VERSION 5.7 ;
BUSBITCHARS "[]" ;
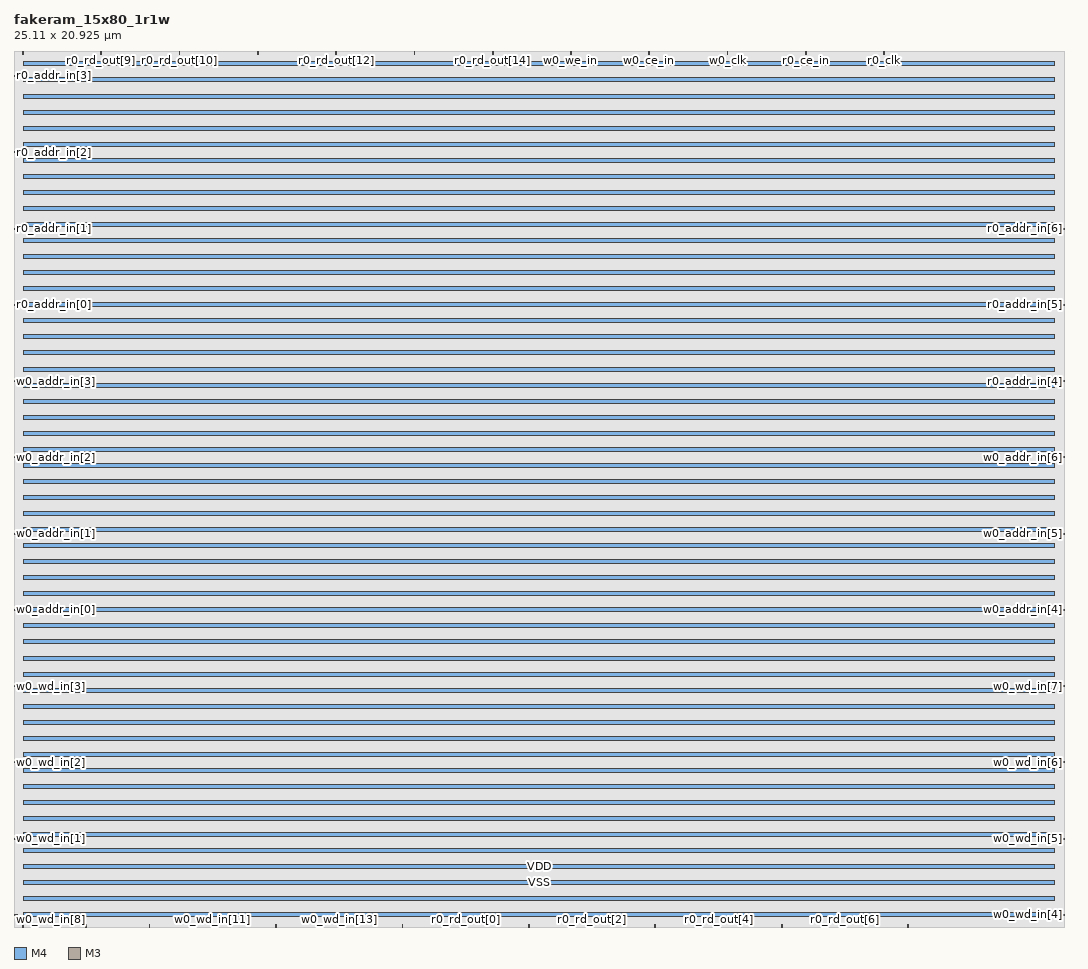
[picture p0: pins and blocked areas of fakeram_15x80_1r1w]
MACRO fakeram_15x80_1r1w
  FOREIGN fakeram_15x80_1r1w 0 0 ;
  SYMMETRY X Y R90 ;
  SIZE 25.110 BY 20.925 ;
  CLASS BLOCK ;
  PIN w0_wd_in[0]
    DIRECTION INPUT ;
    USE SIGNAL ;
    SHAPE ABUTMENT ;
    PORT
      LAYER M4 ;
      RECT 0.000 0.276 0.072 0.300 ;
    END
  END w0_wd_in[0]
  PIN w0_wd_in[1]
    DIRECTION INPUT ;
    USE SIGNAL ;
    SHAPE ABUTMENT ;
    PORT
      LAYER M4 ;
      RECT 0.000 2.100 0.072 2.124 ;
    END
  END w0_wd_in[1]
  PIN w0_wd_in[2]
    DIRECTION INPUT ;
    USE SIGNAL ;
    SHAPE ABUTMENT ;
    PORT
      LAYER M4 ;
      RECT 0.000 3.924 0.072 3.948 ;
    END
  END w0_wd_in[2]
  PIN w0_wd_in[3]
    DIRECTION INPUT ;
    USE SIGNAL ;
    SHAPE ABUTMENT ;
    PORT
      LAYER M4 ;
      RECT 0.000 5.748 0.072 5.772 ;
    END
  END w0_wd_in[3]
  PIN w0_wd_in[4]
    DIRECTION INPUT ;
    USE SIGNAL ;
    SHAPE ABUTMENT ;
    PORT
      LAYER M4 ;
      RECT 25.038 0.276 25.110 0.300 ;
    END
  END w0_wd_in[4]
  PIN w0_wd_in[5]
    DIRECTION INPUT ;
    USE SIGNAL ;
    SHAPE ABUTMENT ;
    PORT
      LAYER M4 ;
      RECT 25.038 2.100 25.110 2.124 ;
    END
  END w0_wd_in[5]
  PIN w0_wd_in[6]
    DIRECTION INPUT ;
    USE SIGNAL ;
    SHAPE ABUTMENT ;
    PORT
      LAYER M4 ;
      RECT 25.038 3.924 25.110 3.948 ;
    END
  END w0_wd_in[6]
  PIN w0_wd_in[7]
    DIRECTION INPUT ;
    USE SIGNAL ;
    SHAPE ABUTMENT ;
    PORT
      LAYER M4 ;
      RECT 25.038 5.748 25.110 5.772 ;
    END
  END w0_wd_in[7]
  PIN w0_wd_in[8]
    DIRECTION INPUT ;
    USE SIGNAL ;
    SHAPE ABUTMENT ;
    PORT
      LAYER M3 ;
      RECT 0.207 0.000 0.225 0.054 ;
    END
  END w0_wd_in[8]
  PIN w0_wd_in[9]
    DIRECTION INPUT ;
    USE SIGNAL ;
    SHAPE ABUTMENT ;
    PORT
      LAYER M3 ;
      RECT 1.719 0.000 1.737 0.054 ;
    END
  END w0_wd_in[9]
  PIN w0_wd_in[10]
    DIRECTION INPUT ;
    USE SIGNAL ;
    SHAPE ABUTMENT ;
    PORT
      LAYER M3 ;
      RECT 3.231 0.000 3.249 0.054 ;
    END
  END w0_wd_in[10]
  PIN w0_wd_in[11]
    DIRECTION INPUT ;
    USE SIGNAL ;
    SHAPE ABUTMENT ;
    PORT
      LAYER M3 ;
      RECT 4.743 0.000 4.761 0.054 ;
    END
  END w0_wd_in[11]
  PIN w0_wd_in[12]
    DIRECTION INPUT ;
    USE SIGNAL ;
    SHAPE ABUTMENT ;
    PORT
      LAYER M3 ;
      RECT 6.255 0.000 6.273 0.054 ;
    END
  END w0_wd_in[12]
  PIN w0_wd_in[13]
    DIRECTION INPUT ;
    USE SIGNAL ;
    SHAPE ABUTMENT ;
    PORT
      LAYER M3 ;
      RECT 7.767 0.000 7.785 0.054 ;
    END
  END w0_wd_in[13]
  PIN w0_wd_in[14]
    DIRECTION INPUT ;
    USE SIGNAL ;
    SHAPE ABUTMENT ;
    PORT
      LAYER M3 ;
      RECT 9.279 0.000 9.297 0.054 ;
    END
  END w0_wd_in[14]
  PIN r0_rd_out[0]
    DIRECTION OUTPUT ;
    USE SIGNAL ;
    SHAPE ABUTMENT ;
    PORT
      LAYER M3 ;
      RECT 10.791 0.000 10.809 0.054 ;
    END
  END r0_rd_out[0]
  PIN r0_rd_out[1]
    DIRECTION OUTPUT ;
    USE SIGNAL ;
    SHAPE ABUTMENT ;
    PORT
      LAYER M3 ;
      RECT 12.303 0.000 12.321 0.054 ;
    END
  END r0_rd_out[1]
  PIN r0_rd_out[2]
    DIRECTION OUTPUT ;
    USE SIGNAL ;
    SHAPE ABUTMENT ;
    PORT
      LAYER M3 ;
      RECT 13.815 0.000 13.833 0.054 ;
    END
  END r0_rd_out[2]
  PIN r0_rd_out[3]
    DIRECTION OUTPUT ;
    USE SIGNAL ;
    SHAPE ABUTMENT ;
    PORT
      LAYER M3 ;
      RECT 15.327 0.000 15.345 0.054 ;
    END
  END r0_rd_out[3]
  PIN r0_rd_out[4]
    DIRECTION OUTPUT ;
    USE SIGNAL ;
    SHAPE ABUTMENT ;
    PORT
      LAYER M3 ;
      RECT 16.839 0.000 16.857 0.054 ;
    END
  END r0_rd_out[4]
  PIN r0_rd_out[5]
    DIRECTION OUTPUT ;
    USE SIGNAL ;
    SHAPE ABUTMENT ;
    PORT
      LAYER M3 ;
      RECT 18.351 0.000 18.369 0.054 ;
    END
  END r0_rd_out[5]
  PIN r0_rd_out[6]
    DIRECTION OUTPUT ;
    USE SIGNAL ;
    SHAPE ABUTMENT ;
    PORT
      LAYER M3 ;
      RECT 19.863 0.000 19.881 0.054 ;
    END
  END r0_rd_out[6]
  PIN r0_rd_out[7]
    DIRECTION OUTPUT ;
    USE SIGNAL ;
    SHAPE ABUTMENT ;
    PORT
      LAYER M3 ;
      RECT 21.375 0.000 21.393 0.054 ;
    END
  END r0_rd_out[7]
  PIN r0_rd_out[8]
    DIRECTION OUTPUT ;
    USE SIGNAL ;
    SHAPE ABUTMENT ;
    PORT
      LAYER M3 ;
      RECT 0.207 20.871 0.225 20.925 ;
    END
  END r0_rd_out[8]
  PIN r0_rd_out[9]
    DIRECTION OUTPUT ;
    USE SIGNAL ;
    SHAPE ABUTMENT ;
    PORT
      LAYER M3 ;
      RECT 2.079 20.871 2.097 20.925 ;
    END
  END r0_rd_out[9]
  PIN r0_rd_out[10]
    DIRECTION OUTPUT ;
    USE SIGNAL ;
    SHAPE ABUTMENT ;
    PORT
      LAYER M3 ;
      RECT 3.951 20.871 3.969 20.925 ;
    END
  END r0_rd_out[10]
  PIN r0_rd_out[11]
    DIRECTION OUTPUT ;
    USE SIGNAL ;
    SHAPE ABUTMENT ;
    PORT
      LAYER M3 ;
      RECT 5.823 20.871 5.841 20.925 ;
    END
  END r0_rd_out[11]
  PIN r0_rd_out[12]
    DIRECTION OUTPUT ;
    USE SIGNAL ;
    SHAPE ABUTMENT ;
    PORT
      LAYER M3 ;
      RECT 7.695 20.871 7.713 20.925 ;
    END
  END r0_rd_out[12]
  PIN r0_rd_out[13]
    DIRECTION OUTPUT ;
    USE SIGNAL ;
    SHAPE ABUTMENT ;
    PORT
      LAYER M3 ;
      RECT 9.567 20.871 9.585 20.925 ;
    END
  END r0_rd_out[13]
  PIN r0_rd_out[14]
    DIRECTION OUTPUT ;
    USE SIGNAL ;
    SHAPE ABUTMENT ;
    PORT
      LAYER M3 ;
      RECT 11.439 20.871 11.457 20.925 ;
    END
  END r0_rd_out[14]
  PIN w0_addr_in[0]
    DIRECTION INPUT ;
    USE SIGNAL ;
    SHAPE ABUTMENT ;
    PORT
      LAYER M4 ;
      RECT 0.000 7.572 0.072 7.596 ;
    END
  END w0_addr_in[0]
  PIN w0_addr_in[1]
    DIRECTION INPUT ;
    USE SIGNAL ;
    SHAPE ABUTMENT ;
    PORT
      LAYER M4 ;
      RECT 0.000 9.396 0.072 9.420 ;
    END
  END w0_addr_in[1]
  PIN w0_addr_in[2]
    DIRECTION INPUT ;
    USE SIGNAL ;
    SHAPE ABUTMENT ;
    PORT
      LAYER M4 ;
      RECT 0.000 11.220 0.072 11.244 ;
    END
  END w0_addr_in[2]
  PIN w0_addr_in[3]
    DIRECTION INPUT ;
    USE SIGNAL ;
    SHAPE ABUTMENT ;
    PORT
      LAYER M4 ;
      RECT 0.000 13.044 0.072 13.068 ;
    END
  END w0_addr_in[3]
  PIN w0_addr_in[4]
    DIRECTION INPUT ;
    USE SIGNAL ;
    SHAPE ABUTMENT ;
    PORT
      LAYER M4 ;
      RECT 25.038 7.572 25.110 7.596 ;
    END
  END w0_addr_in[4]
  PIN w0_addr_in[5]
    DIRECTION INPUT ;
    USE SIGNAL ;
    SHAPE ABUTMENT ;
    PORT
      LAYER M4 ;
      RECT 25.038 9.396 25.110 9.420 ;
    END
  END w0_addr_in[5]
  PIN w0_addr_in[6]
    DIRECTION INPUT ;
    USE SIGNAL ;
    SHAPE ABUTMENT ;
    PORT
      LAYER M4 ;
      RECT 25.038 11.220 25.110 11.244 ;
    END
  END w0_addr_in[6]
  PIN r0_addr_in[0]
    DIRECTION INPUT ;
    USE SIGNAL ;
    SHAPE ABUTMENT ;
    PORT
      LAYER M4 ;
      RECT 0.000 14.868 0.072 14.892 ;
    END
  END r0_addr_in[0]
  PIN r0_addr_in[1]
    DIRECTION INPUT ;
    USE SIGNAL ;
    SHAPE ABUTMENT ;
    PORT
      LAYER M4 ;
      RECT 0.000 16.692 0.072 16.716 ;
    END
  END r0_addr_in[1]
  PIN r0_addr_in[2]
    DIRECTION INPUT ;
    USE SIGNAL ;
    SHAPE ABUTMENT ;
    PORT
      LAYER M4 ;
      RECT 0.000 18.516 0.072 18.540 ;
    END
  END r0_addr_in[2]
  PIN r0_addr_in[3]
    DIRECTION INPUT ;
    USE SIGNAL ;
    SHAPE ABUTMENT ;
    PORT
      LAYER M4 ;
      RECT 0.000 20.340 0.072 20.364 ;
    END
  END r0_addr_in[3]
  PIN r0_addr_in[4]
    DIRECTION INPUT ;
    USE SIGNAL ;
    SHAPE ABUTMENT ;
    PORT
      LAYER M4 ;
      RECT 25.038 13.044 25.110 13.068 ;
    END
  END r0_addr_in[4]
  PIN r0_addr_in[5]
    DIRECTION INPUT ;
    USE SIGNAL ;
    SHAPE ABUTMENT ;
    PORT
      LAYER M4 ;
      RECT 25.038 14.868 25.110 14.892 ;
    END
  END r0_addr_in[5]
  PIN r0_addr_in[6]
    DIRECTION INPUT ;
    USE SIGNAL ;
    SHAPE ABUTMENT ;
    PORT
      LAYER M4 ;
      RECT 25.038 16.692 25.110 16.716 ;
    END
  END r0_addr_in[6]
  PIN w0_we_in
    DIRECTION INPUT ;
    USE SIGNAL ;
    SHAPE ABUTMENT ;
    PORT
      LAYER M3 ;
      RECT 13.311 20.871 13.329 20.925 ;
    END
  END w0_we_in
  PIN w0_ce_in
    DIRECTION INPUT ;
    USE SIGNAL ;
    SHAPE ABUTMENT ;
    PORT
      LAYER M3 ;
      RECT 15.183 20.871 15.201 20.925 ;
    END
  END w0_ce_in
  PIN w0_clk
    DIRECTION INPUT ;
    USE SIGNAL ;
    SHAPE ABUTMENT ;
    PORT
      LAYER M3 ;
      RECT 17.055 20.871 17.073 20.925 ;
    END
  END w0_clk
  PIN r0_ce_in
    DIRECTION INPUT ;
    USE SIGNAL ;
    SHAPE ABUTMENT ;
    PORT
      LAYER M3 ;
      RECT 18.927 20.871 18.945 20.925 ;
    END
  END r0_ce_in
  PIN r0_clk
    DIRECTION INPUT ;
    USE SIGNAL ;
    SHAPE ABUTMENT ;
    PORT
      LAYER M3 ;
      RECT 20.799 20.871 20.817 20.925 ;
    END
  END r0_clk
  PIN VSS
    DIRECTION INOUT ;
    USE GROUND ;
    PORT
      LAYER M4 ;
      RECT 0.216 0.240 24.894 0.336 ;
      RECT 0.216 1.008 24.894 1.104 ;
      RECT 0.216 1.776 24.894 1.872 ;
      RECT 0.216 2.544 24.894 2.640 ;
      RECT 0.216 3.312 24.894 3.408 ;
      RECT 0.216 4.080 24.894 4.176 ;
      RECT 0.216 4.848 24.894 4.944 ;
      RECT 0.216 5.616 24.894 5.712 ;
      RECT 0.216 6.384 24.894 6.480 ;
      RECT 0.216 7.152 24.894 7.248 ;
      RECT 0.216 7.920 24.894 8.016 ;
      RECT 0.216 8.688 24.894 8.784 ;
      RECT 0.216 9.456 24.894 9.552 ;
      RECT 0.216 10.224 24.894 10.320 ;
      RECT 0.216 10.992 24.894 11.088 ;
      RECT 0.216 11.760 24.894 11.856 ;
      RECT 0.216 12.528 24.894 12.624 ;
      RECT 0.216 13.296 24.894 13.392 ;
      RECT 0.216 14.064 24.894 14.160 ;
      RECT 0.216 14.832 24.894 14.928 ;
      RECT 0.216 15.600 24.894 15.696 ;
      RECT 0.216 16.368 24.894 16.464 ;
      RECT 0.216 17.136 24.894 17.232 ;
      RECT 0.216 17.904 24.894 18.000 ;
      RECT 0.216 18.672 24.894 18.768 ;
      RECT 0.216 19.440 24.894 19.536 ;
      RECT 0.216 20.208 24.894 20.304 ;
    END
  END VSS
  PIN VDD
    DIRECTION INOUT ;
    USE POWER ;
    PORT
      LAYER M4 ;
      RECT 0.216 0.624 24.894 0.720 ;
      RECT 0.216 1.392 24.894 1.488 ;
      RECT 0.216 2.160 24.894 2.256 ;
      RECT 0.216 2.928 24.894 3.024 ;
      RECT 0.216 3.696 24.894 3.792 ;
      RECT 0.216 4.464 24.894 4.560 ;
      RECT 0.216 5.232 24.894 5.328 ;
      RECT 0.216 6.000 24.894 6.096 ;
      RECT 0.216 6.768 24.894 6.864 ;
      RECT 0.216 7.536 24.894 7.632 ;
      RECT 0.216 8.304 24.894 8.400 ;
      RECT 0.216 9.072 24.894 9.168 ;
      RECT 0.216 9.840 24.894 9.936 ;
      RECT 0.216 10.608 24.894 10.704 ;
      RECT 0.216 11.376 24.894 11.472 ;
      RECT 0.216 12.144 24.894 12.240 ;
      RECT 0.216 12.912 24.894 13.008 ;
      RECT 0.216 13.680 24.894 13.776 ;
      RECT 0.216 14.448 24.894 14.544 ;
      RECT 0.216 15.216 24.894 15.312 ;
      RECT 0.216 15.984 24.894 16.080 ;
      RECT 0.216 16.752 24.894 16.848 ;
      RECT 0.216 17.520 24.894 17.616 ;
      RECT 0.216 18.288 24.894 18.384 ;
      RECT 0.216 19.056 24.894 19.152 ;
      RECT 0.216 19.824 24.894 19.920 ;
      RECT 0.216 20.592 24.894 20.688 ;
    END
  END VDD
  OBS
    LAYER M1 ;
    RECT 0 0 25.110 20.925 ;
    LAYER M2 ;
    RECT 0 0 25.110 20.925 ;
    LAYER M3 ;
    RECT 0 0 25.110 20.925 ;
    LAYER M4 ;
    RECT 0 0 25.110 20.925 ;
  END
END fakeram_15x80_1r1w

END LIBRARY
